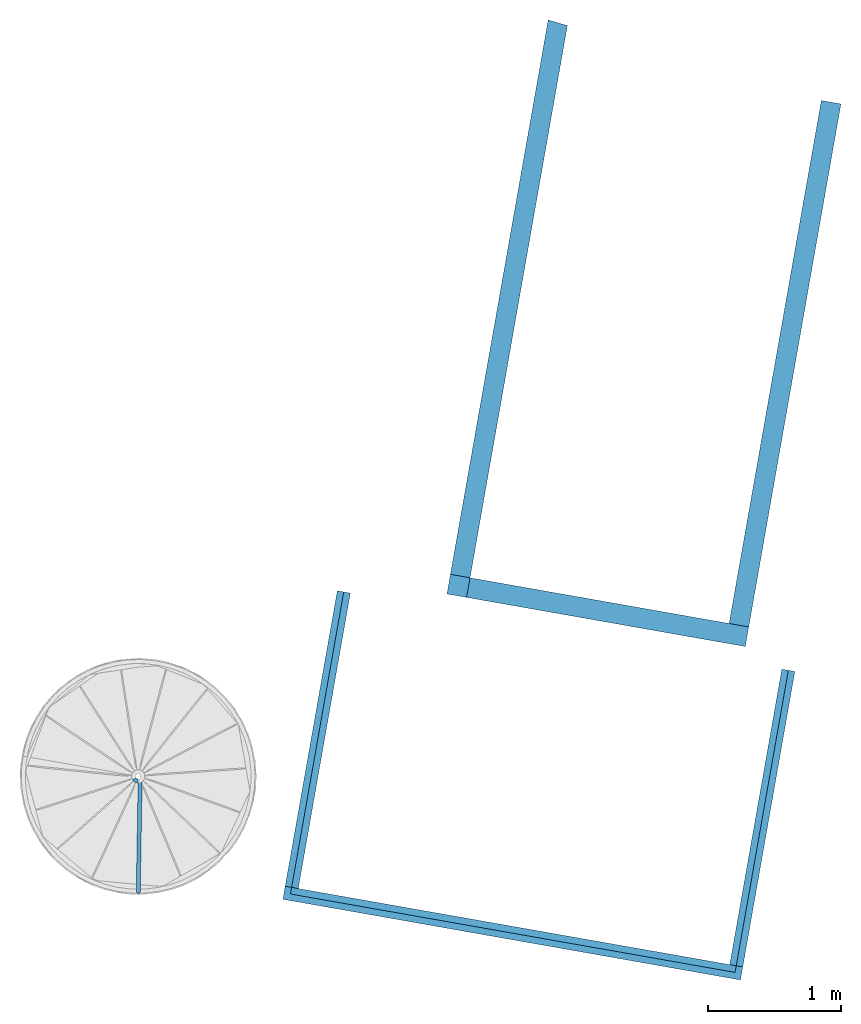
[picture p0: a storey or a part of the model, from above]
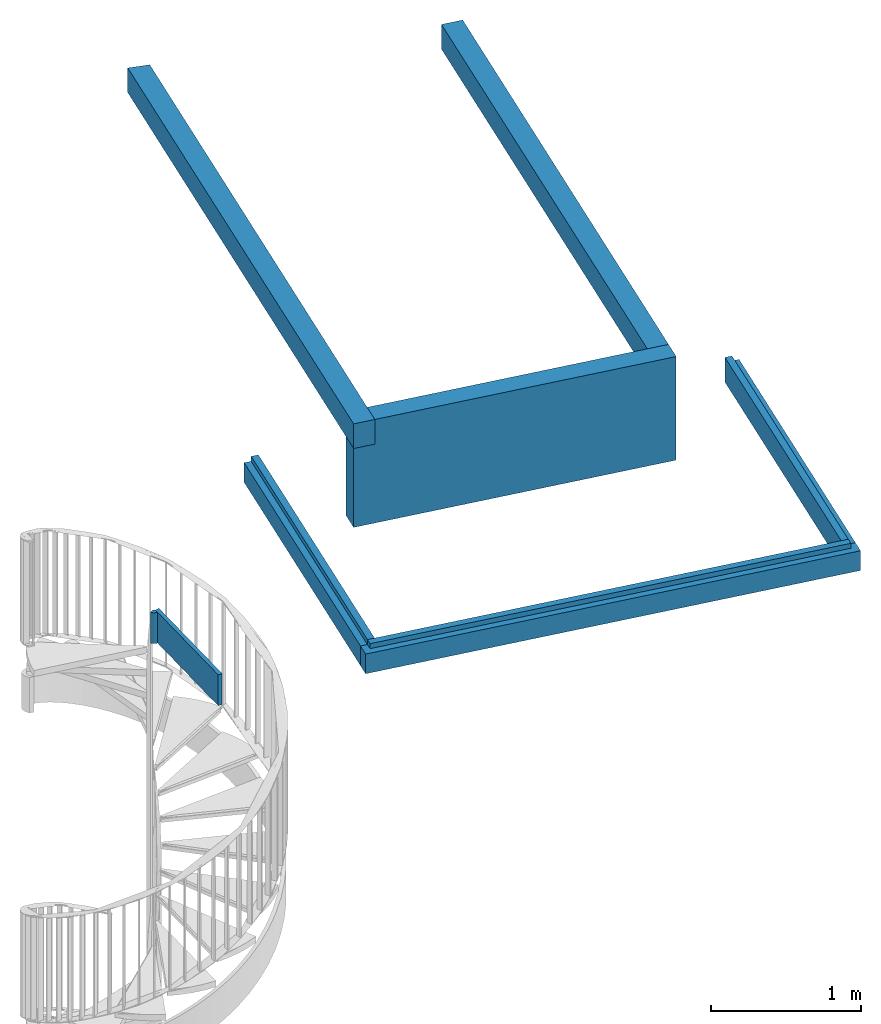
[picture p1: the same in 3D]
Properties of the parts of a building model (IFC2X3), part 2 of 3

# IfcPlate: 31_CWP_glas_1 (26)
Name (System Panel:31_CWP_glas_1:...) | Group
2317196 | Model Group:vliesgevel C:2317233
2317197 | Model Group:vliesgevel C:2317233
2317198 | Model Group:vliesgevel C:2317233
2317199 | Model Group:vliesgevel C:2317233
2317200 | Model Group:vliesgevel C:2317233
2317214 | Model Group:vliesgevel C:2317233
2317215 | Model Group:vliesgevel C:2317233
2317216 | Model Group:vliesgevel C:2317233
2317217 | Model Group:vliesgevel C:2317233
2317218 | Model Group:vliesgevel C:2317233
2317219 | Model Group:vliesgevel C:2317233
2940402 | Model Group:vliesgevel A:2917414
2940415 | Model Group:vliesgevel A:2917414
2940420 | Model Group:vliesgevel A:2917414
2940421 | Model Group:vliesgevel A:2917414
2940422 | Model Group:vliesgevel A:2917414
2940423 | Model Group:vliesgevel A:2917414
2940434 | Model Group:vliesgevel A:2917414
2940435 | Model Group:vliesgevel A:2917414
2940436 | Model Group:vliesgevel A:2917414
2940437 | Model Group:vliesgevel A:2917414

# IfcPlate: 31_CWP_glas_2 (23)
Type - PredefinedType: CURTAIN_PANEL; Material: <Unnamed> 24 mm
Type - Pset_PlateCommon - IsExternal: no; Reference: 31_CWP_glas_2
Type - Pset_ProductRequirements - Category: Curtain Panels
Type - Pset_QuantityTakeOff - Reference: 31_CWP_glas_2
Classification: 31.10 buitenwandopeningen; niet gevuld, algemeen (verzamelniveau) (Uniformat)
Pset_PlateCommon - IsExternal: yes
Name (System Panel:31_CWP_glas_2:...) | In | Group
2287267 | 01 eerste verdieping | Model Group:H07:2287249
2760791 | 00 begane grond | Model Group:H08:2161338
2760801 | 00 begane grond | Model Group:H08:2161338
2760811 | 00 begane grond | Model Group:H08:2161338
2760821 | 00 begane grond | Model Group:H08:2161338
2760831 | 00 begane grond | Model Group:H08:2161338
2760841 | 00 begane grond | Model Group:H08:2161338
2760851 | 00 begane grond | Model Group:H08:2161338
2760861 | 00 begane grond | Model Group:H08:2161338
2760871 | 00 begane grond | Model Group:H08:2161338
2760881 | 00 begane grond | Model Group:H08:2161338
2760891 | 00 begane grond | Model Group:H08:2161338
2761306 | 02 tweede verdieping | Model Group:H09:1979223
2761316 | 02 tweede verdieping | Model Group:H09:1979223
2763742 | 02 tweede verdieping | Model Group:H10:2055879
2763752 | 02 tweede verdieping | Model Group:H10:2055879
2763762 | 02 tweede verdieping | Model Group:H10:2055879
2763772 | 02 tweede verdieping | Model Group:H10:2055879
2763782 | 02 tweede verdieping | Model Group:H10:2055879
2763792 | 02 tweede verdieping | Model Group:H10:2055879
2764323 | 02 tweede verdieping | Model Group:H11:2764105
2764333 | 02 tweede verdieping | Model Group:H11:2764105
2764343 | 02 tweede verdieping | Model Group:H11:2764105

# IfcPlate: 32_CWP_glas (14)
In: 00 begane grond
Type - PredefinedType: CURTAIN_PANEL; Material: <Unnamed> 24 mm
Type - Pset_PlateCommon - IsExternal: no; Reference: 32_CWP_glas
Type - Pset_ProductRequirements - Category: Curtain Panels
Type - Pset_QuantityTakeOff - Reference: 32_CWP_glas
Pset_PlateCommon - IsExternal: yes
Name (System Panel:32_CWP_glas:...) | Classification | Group
1745525 | 32.40 binnenwandopeningen; gevuld met puien, algemeen (verzamelniveau) (Uniformat) | Model Group:Vliesgevel B:2773624
2534468 | 32.40 binnenwandopeningen; gevuld met puien, algemeen (verzamelniveau) (Uniformat) | Model Group:Vliesgevel B:2773624
2532248 | 32.40 binnenwandopeningen; gevuld met puien, algemeen (verzamelniveau) (Uniformat) | Model Group:Vliesgevel B:2773624
2534469 | 32.40 binnenwandopeningen; gevuld met puien, algemeen (verzamelniveau) (Uniformat) | Model Group:Vliesgevel B:2773624
2532249 | 32.40 binnenwandopeningen; gevuld met puien, algemeen (verzamelniveau) (Uniformat) | Model Group:Vliesgevel B:2773624
2534730 | 32.40 binnenwandopeningen; gevuld met puien, algemeen (verzamelniveau) (Uniformat) | Model Group:Vliesgevel B:2773624
2533499 | 32.40 binnenwandopeningen; gevuld met puien, algemeen (verzamelniveau) (Uniformat) | Model Group:Vliesgevel B:2773624
2534470 | 32.40 binnenwandopeningen; gevuld met puien, algemeen (verzamelniveau) (Uniformat) | Model Group:Vliesgevel B:2773624
2533500 | 32.40 binnenwandopeningen; gevuld met puien, algemeen (verzamelniveau) (Uniformat) | Model Group:Vliesgevel B:2773624
2534731 | 32.40 binnenwandopeningen; gevuld met puien, algemeen (verzamelniveau) (Uniformat) | Model Group:Vliesgevel B:2773624
1745975 | 32 binnenwandopeningen (Uniformat)
1745978 | 32 binnenwandopeningen (Uniformat)
1745980 | 32 binnenwandopeningen (Uniformat)
1766173 | 32 binnenwandopeningen (Uniformat)

# IfcRailing: Railing:NLRS_90_RA_LB_hekwerk panelen_laag (2)
Classification: 34.11 balustrades en leuningen; balustrades, binnenbalustrades (Uniformat); Material: h2_staal_gen; Group: Model Group:trap naar kelder:2174486
Pset_ProductRequirements - Category: Railings
Pset_QuantityTakeOff - Reference: NLRS_90_RA_LB_hekwerk panelen_laag
Pset_RailingCommon - IsExternal: no; Reference: NLRS_90_RA_LB_hekwerk panelen_laag; Height: 1219.2 mm
Name (Railing:NLRS_90_RA_LB_hekwerk panelen_laag:...) | In
2174470 | -1 kelder
2174483 | 00 begane grond

# IfcRailing: Railing:NLRS_90_RA_LB_hekwerk spijlen staal, Railing:NLRS_90_RA_LB_hekwerk spijlen staal:2887061
In: 02 tweede verdieping
Classification: 34.11 balustrades en leuningen; balustrades, binnenbalustrades (Uniformat); Material: h2_staal_gen
Pset_ProductRequirements - Category: Railings
Pset_QuantityTakeOff - Reference: NLRS_90_RA_LB_hekwerk spijlen staal
Pset_RailingCommon - IsExternal: no; Reference: NLRS_90_RA_LB_hekwerk spijlen staal; Height: 1219.2 mm

# IfcRailing: Railing:NLRS_90_RA_LB_hekwerk spijlen staal + bordes strip, Railing:NLRS_90_RA_LB_hekwerk spijlen staal + bordes strip:2925256
In: 02 tweede verdieping
Classification: 34.11 balustrades en leuningen; balustrades, binnenbalustrades (Uniformat); Material: h2_staal_gen
Pset_ProductRequirements - Category: Railings
Pset_QuantityTakeOff - Reference: NLRS_90_RA_LB_hekwerk spijlen staal + bordes strip
Pset_RailingCommon - IsExternal: no; Reference: NLRS_90_RA_LB_hekwerk spijlen staal + bordes strip; Height: 1219.2 mm

# IfcRailing: Railing:NLRS_90_RA_LB_hekwerk spijlen staal + trapboom strip, Railing:NLRS_90_RA_LB_hekwerk spijlen staal + trapboom strip:2926586
In: 00 begane grond
Classification: 34.11 balustrades en leuningen; balustrades, binnenbalustrades (Uniformat); Material: h2_staal_gen
Pset_ProductRequirements - Category: Railings
Pset_QuantityTakeOff - Reference: NLRS_90_RA_LB_hekwerk spijlen staal + trapboom strip
Pset_RailingCommon - IsExternal: no; Reference: NLRS_90_RA_LB_hekwerk spijlen staal + trapboom strip; Height: 1219.2 mm

# IfcRailing: Railing:NLRS_90_RA_LB_hekwerk spijlen staal +trapboom (2)
In: 02 tweede verdieping
Classification: 34.11 balustrades en leuningen; balustrades, binnenbalustrades (Uniformat); Material: h2_staal_gen
Pset_ProductRequirements - Category: Railings
Pset_QuantityTakeOff - Reference: NLRS_90_RA_LB_hekwerk spijlen staal +trapboom
Pset_RailingCommon - IsExternal: no; Reference: NLRS_90_RA_LB_hekwerk spijlen staal +trapboom; Height: 1219.2 mm
Name (Railing:NLRS_90_RA_LB_hekwerk spijlen staal +trapboom:...)
2871537
2871541

# IfcRailing: Railing:RBM_RA_glasbalustrade (8)
Classification: C2010400 (Uniformat); Material: Glass_RIPO
Pset_ProductRequirements - Category: Railings
Pset_QuantityTakeOff - Reference: RBM_RA_glasbalustrade
Pset_RailingCommon - IsExternal: no; Reference: RBM_RA_glasbalustrade; Height: 1066.8 mm
Name (Railing:RBM_RA_glasbalustrade:...) | In
2876911 | 02 tweede verdieping
2877435 | 00 begane grond
2878266 | 02 tweede verdieping
2878645 | 02 tweede verdieping
2879326 | 02 tweede verdieping
2879408 | 02 tweede verdieping
2879637 | 02 tweede verdieping
2879737 | 02 tweede verdieping

# IfcRailing: Railing:RBM_RA_glasbalustrade 02 TRAP (2)
Classification: C2010400 (Uniformat); Material: Glass_RIPO
Pset_ProductRequirements - Category: Railings
Pset_QuantityTakeOff - Reference: RBM_RA_glasbalustrade 02 TRAP
Pset_RailingCommon - IsExternal: no; Reference: RBM_RA_glasbalustrade 02 TRAP; Height: 1066.8 mm
Name (Railing:RBM_RA_glasbalustrade 02 TRAP:...) | In
2877431 | 00 begane grond
2878579 | 01 eerste verdieping

# IfcRailing: Railing:RBM_RA_handleuning (3)
Classification: C2010400 (Uniformat)
Pset_ProductRequirements - Category: Railings
Pset_QuantityTakeOff - Reference: RBM_RA_handleuning
Pset_RailingCommon - IsExternal: no; Reference: RBM_RA_handleuning; Height: 1066.8 mm
Name (Railing:RBM_RA_handleuning:...) | In
2879164 | 02 tweede verdieping
2879217 | 02 tweede verdieping
2879233 | 01 eerste verdieping

# IfcRoof: Basic Roof:Dak_isolatie goot, Basic Roof:Dak_isolatie goot:2599447
In: 03 dak
Classification: 27.10 daken; niet constructief, algemeen (verzamelniveau) (Uniformat)
Pset_ElementShading - Roughness: 304.8 mm
Pset_ProductRequirements - Category: Roofs
Pset_QuantityTakeOff - Reference: Dak_isolatie goot
Pset_RoofCommon - IsExternal: yes; Reference: Dak_isolatie goot; ProjectedArea: 5.72349 m2; TotalArea: 5.73957 m2

# IfcRoof: Basic Roof:RBM_27_RO_dakisolatie met afwerking_240mm (2)
Classification: 27.10 daken; niet constructief, algemeen (verzamelniveau) (Uniformat)
Pset_ElementShading - Roughness: 304.8 mm
Pset_ProductRequirements - Category: Roofs
Pset_QuantityTakeOff - Reference: RBM_27_RO_dakisolatie met afwerking_240mm
Pset_RoofCommon - IsExternal: yes; Reference: RBM_27_RO_dakisolatie met afwerking_240mm
Name (Basic Roof:RBM_27_RO_dakisolatie met afwerking_240mm:...) | In | ProjectedArea (m2) | TotalArea (m2)
2319589 | 03 dak | 268.647 | 269.401
2454118 | 02 tweede verdieping | 3.34901 | 3.34901

# IfcRoof: Basic Roof:RBM_27_RO_dakrand_gelamineerd, Basic Roof:RBM_27_RO_dakrand_gelamineerd:2143979
In: 03 dak
Classification: 47.23 dakafwerkingen; bekledingen, luifel bekledingen (Uniformat); Material: hout_accoya_gelamineerd 600 mm
Pset_ElementShading - Roughness: 304.8 mm
Pset_ProductRequirements - Category: Roofs
Pset_QuantityTakeOff - Reference: RBM_27_RO_dakrand_gelamineerd
Pset_RoofCommon - IsExternal: yes; Reference: RBM_27_RO_dakrand_gelamineerd; ProjectedArea: 449.378 m2; TotalArea: 9.75975 m2

# IfcRoof: Sloped Glazing:dakbalken (2)
In: 03 dak
Type - Pset_CurtainWallCommon - IsExternal: yes; Reference: dakbalken
Type - Pset_ProductRequirements - Category: Roofs
Type - Pset_QuantityTakeOff - Reference: dakbalken
Classification: 27.23 daken; constructief, luifels (Uniformat)
Pset_RoofCommon - IsExternal: yes; Reference: dakbalken
Name (Sloped Glazing:dakbalken:...) | ProjectedArea (m2)
2777888 | 54.3172
2777893 | 105.253

# IfcSlab: Basic Roof:Dak_isolatie goot, Basic Roof:Dak_isolatie goot:2599447
In: 03 dak
PredefinedType: ROOF; Classification: 27.10 daken; niet constructief, algemeen (verzamelniveau) (Uniformat); Material: RBM_n7_dakisolatie_80 80 mm
Pset_ElementShading - Roughness: 304.8 mm
Pset_ProductRequirements - Category: Roofs
Pset_QuantityTakeOff - Reference: Dak_isolatie goot; sets with these values: 2
Pset_SlabCommon - IsExternal: yes; Reference: Dak_isolatie goot; ThermalTransmittance: 1000000000000000019884624838656 kg/K/s3; PitchAngle: 4.29718 deg

# IfcSlab: Basic Roof:RBM_27_RO_dakisolatie met afwerking_240mm (2)
PredefinedType: ROOF; Classification: 27.10 daken; niet constructief, algemeen (verzamelniveau) (Uniformat); Material: RBM_n7_dakisolatie_240mm 240 mm
Pset_ElementShading - Roughness: 304.8 mm
Pset_ProductRequirements - Category: Roofs
Pset_QuantityTakeOff - Reference: RBM_27_RO_dakisolatie met afwerking_240mm; sets with these values: 2
Pset_SlabCommon - IsExternal: yes; Reference: RBM_27_RO_dakisolatie met afwerking_240mm; ThermalTransmittance: 1000000000000000019884624838656 kg/K/s3
Name (Basic Roof:RBM_27_RO_dakisolatie met afwerking_240mm:...) | In | PitchAngle (deg)
2319589 | 03 dak | 4.29718
2454118 | 02 tweede verdieping | 0

# IfcSlab: Floor:RBM_23_FL_Fermacell_zwevende_dekvloer (2)
In: 01 eerste verdieping
Type - PredefinedType: FLOOR; Material: vloerafwerking pvc 10 mm, Zwevende dekvloer Fermacell 35 mm
Type - Pset_ElementShading - Roughness: 304.8 mm
Type - Pset_ProductRequirements - Category: Floors
Type - Pset_QuantityTakeOff - Reference: RBM_23_FL_Fermacell_zwevende_dekvloer
Type - Pset_ReinforcementBarPitchOfSlab - Description: Fermacell zwevende dekvloer; Reference: RBM_23_FL_Fermacell_zwevende_dekvloer
Type - Pset_SlabCommon - IsExternal: no; Reference: RBM_23_FL_Fermacell_zwevende_dekvloer; ThermalTransmittance: 104.6 kg/K/s3
Classification: 23.21 vloeren; constructief, vrijdragende vloeren (Uniformat)
Pset_SlabCommon - LoadBearing: no; PitchAngle: 0 deg
Name (Floor:RBM_23_FL_Fermacell_zwevende_dekvloer:...)
2631502
2645933

# IfcSlab: Floor:RBM_23_FL_balklaag dak_71x246mm h.o.h.400mm, Floor:RBM_23_FL_balklaag dak_71x246mm h.o.h.400mm:2453909
In: 02 tweede verdieping
Type - PredefinedType: FLOOR; Material: RBM_i2_hout_vuren_gen 246 mm
Type - Pset_ElementShading - Roughness: 304.8 mm
Type - Pset_ProductRequirements - Category: Floors
Type - Pset_QuantityTakeOff - Reference: RBM_23_FL_balklaag dak_71x246mm h.o.h.400mm
Type - Pset_ReinforcementBarPitchOfSlab - Description: vloer, generiek; Reference: RBM_23_FL_balklaag dak_71x246mm h.o.h.400mm
Type - Pset_SlabCommon - IsExternal: no; Reference: RBM_23_FL_balklaag dak_71x246mm h.o.h.400mm; ThermalTransmittance: 0.487805 kg/K/s3
Classification: 23.20 vloeren; constructief, algemeen (verzamelniveau) (Uniformat)
Pset_SlabCommon - LoadBearing: no; PitchAngle: 0 deg

# IfcSlab: Floor:RBM_23_FL_balklaag dak_71x271, h.o.h. 400 (3)
Type - PredefinedType: FLOOR; Material: ISR_Multiplex 18 mm, RBM_i2_hout_vuren_gen 271 mm
Type - Pset_ElementShading - Roughness: 304.8 mm
Type - Pset_ProductRequirements - Category: Floors
Type - Pset_QuantityTakeOff - Reference: RBM_23_FL_balklaag dak_71x271, h.o.h. 400
Type - Pset_ReinforcementBarPitchOfSlab - Description: vloer, generiek; Reference: RBM_23_FL_balklaag dak_71x271, h.o.h. 400
Type - Pset_SlabCommon - IsExternal: no; Reference: RBM_23_FL_balklaag dak_71x271, h.o.h. 400; ThermalTransmittance: 0.442804 kg/K/s3
Classification: 23.20 vloeren; constructief, algemeen (verzamelniveau) (Uniformat)
Pset_SlabCommon - LoadBearing: no; PitchAngle: 0 deg
Name (Floor:RBM_23_FL_balklaag dak_71x271, h.o.h. 400:...) | In
1974393 | 02 tweede verdieping
1977292 | 01 eerste verdieping
2748788 | 01 eerste verdieping

# IfcSlab: Floor:RBM_23_FL_dakisolatie 30 mm (2)
In: 01 eerste verdieping
Type - PredefinedType: FLOOR; Material: RBM_n7_dakisolatie_gen 50 mm
Type - Pset_ElementShading - Roughness: 304.8 mm
Type - Pset_ProductRequirements - Category: Floors
Type - Pset_QuantityTakeOff - Reference: RBM_23_FL_dakisolatie 30 mm
Type - Pset_ReinforcementBarPitchOfSlab - Description: vloer, generiek; Reference: RBM_23_FL_dakisolatie 30 mm
Type - Pset_SlabCommon - IsExternal: no; Reference: RBM_23_FL_dakisolatie 30 mm
Classification: 23.20 vloeren; constructief, algemeen (verzamelniveau) (Uniformat)
Pset_SlabCommon - LoadBearing: no; PitchAngle: 0 deg
Name (Floor:RBM_23_FL_dakisolatie 30 mm:...)
2748825
2749276

# IfcSlab: Floor:RBM_23_FL_dakisolatie 30 mm afschot 15mm/m1, Floor:RBM_23_FL_dakisolatie 30 mm afschot 15mm/m1:2749066
In: 02 tweede verdieping
Type - PredefinedType: FLOOR
Type - Pset_ElementShading - Roughness: 304.8 mm
Type - Pset_ProductRequirements - Category: Floors
Type - Pset_QuantityTakeOff - Reference: RBM_23_FL_dakisolatie 30 mm afschot 15mm/m1
Type - Pset_ReinforcementBarPitchOfSlab - Description: vloer, generiek; Reference: RBM_23_FL_dakisolatie 30 mm afschot 15mm/m1
Type - Pset_SlabCommon - IsExternal: no; Reference: RBM_23_FL_dakisolatie 30 mm afschot 15mm/m1
Classification: 23.20 vloeren; constructief, algemeen (verzamelniveau) (Uniformat); Material: RBM_n7_dakisolatie_gen
Pset_SlabCommon - LoadBearing: no

# IfcSlab: Floor:RBM_23_FL_gewapende druklaag gevlinderd (2)
In: 00 begane grond
Type - PredefinedType: FLOOR; Material: RBM_f2_beton_ihwg C20-25 80 mm
Type - Pset_ElementShading - Roughness: 304.8 mm
Type - Pset_ProductRequirements - Category: Floors
Type - Pset_QuantityTakeOff - Reference: RBM_23_FL_gewapende druklaag gevlinderd
Type - Pset_ReinforcementBarPitchOfSlab - Description: vloer, generiek; Reference: RBM_23_FL_gewapende druklaag gevlinderd
Type - Pset_SlabCommon - IsExternal: no; Reference: RBM_23_FL_gewapende druklaag gevlinderd; ThermalTransmittance: 13.075 kg/K/s3
Classification: 23.20 vloeren; constructief, algemeen (verzamelniveau) (Uniformat)
Pset_SlabCommon - LoadBearing: no; PitchAngle: 0 deg
Name (Floor:RBM_23_FL_gewapende druklaag gevlinderd:...)
2798566
2936558

# IfcSlab: Floor:RBM_23_FL_gewapende druklaag gevlinderd+ afwerking (2)
In: 00 begane grond
Type - PredefinedType: FLOOR; Material: vloerafwerking pvc 10 mm, RBM_f2_beton_ihwg C20-25 80 mm
Type - Pset_ElementShading - Roughness: 304.8 mm
Type - Pset_ProductRequirements - Category: Floors
Type - Pset_QuantityTakeOff - Reference: RBM_23_FL_gewapende druklaag gevlinderd+ afwerking
Type - Pset_ReinforcementBarPitchOfSlab - Description: vloer, generiek; Reference: RBM_23_FL_gewapende druklaag gevlinderd+ afwerking
Type - Pset_SlabCommon - IsExternal: no; Reference: RBM_23_FL_gewapende druklaag gevlinderd+ afwerking; ThermalTransmittance: 11.6222 kg/K/s3
Classification: 23.20 vloeren; constructief, algemeen (verzamelniveau) (Uniformat)
Pset_SlabCommon - LoadBearing: no; PitchAngle: 0 deg
Name (Floor:RBM_23_FL_gewapende druklaag gevlinderd+ afwerking:...)
2793050
2796847

# IfcSlab: Floor:RBM_23_FL_gewapende druklaag gevlinderd+ afwerking, Floor:RBM_23_FL_gewapende druklaag gevlinderd+ afwerking:2540512
In: 00 begane grond
Type - PredefinedType: FLOOR
Type - Pset_ElementShading - Roughness: 304.8 mm
Type - Pset_ProductRequirements - Category: Floors
Type - Pset_QuantityTakeOff - Reference: RBM_23_FL_gewapende druklaag gevlinderd+ afwerking
Type - Pset_ReinforcementBarPitchOfSlab - Description: vloer, generiek; Reference: RBM_23_FL_gewapende druklaag gevlinderd+ afwerking
Type - Pset_SlabCommon - IsExternal: no; Reference: RBM_23_FL_gewapende druklaag gevlinderd+ afwerking; ThermalTransmittance: 11.6222 kg/K/s3
Classification: 23.20 vloeren; constructief, algemeen (verzamelniveau) (Uniformat); Material: vloerafwerking pvc, RBM_f2_beton_ihwg C20-25
Pset_SlabCommon - LoadBearing: no

# IfcSlab: Floor:RBM_23_FL_houten kanaalplaat-320mm (2)
Type - PredefinedType: FLOOR; Material: RBM_i4_multiplex_beplating 320 mm
Type - Pset_ElementShading - Roughness: 304.8 mm
Type - Pset_ProductRequirements - Category: Floors
Type - Pset_QuantityTakeOff - Reference: RBM_23_FL_houten kanaalplaat-320mm
Type - Pset_ReinforcementBarPitchOfSlab - Description: prefab houten kanaalplaatvloer, vrijdragend; Reference: RBM_23_FL_houten kanaalplaat-320mm
Type - Pset_SlabCommon - IsExternal: no; Reference: RBM_23_FL_houten kanaalplaat-320mm; ThermalTransmittance: 0.33125 kg/K/s3
Classification: 23.21 vloeren; constructief, vrijdragende vloeren (Uniformat)
Pset_SlabCommon - LoadBearing: no; PitchAngle: 0 deg
Name (Floor:RBM_23_FL_houten kanaalplaat-320mm:...) | In
1655074 | 02 tweede verdieping
1733735 | 03 dak

# IfcSlab: Floor:RBM_23_FL_houten vloer-brug (2)
Type - PredefinedType: FLOOR; Material: traphout 50 mm
Type - Pset_ElementShading - Roughness: 304.8 mm
Type - Pset_ProductRequirements - Category: Floors
Type - Pset_QuantityTakeOff - Reference: RBM_23_FL_houten vloer-brug
Type - Pset_ReinforcementBarPitchOfSlab - Description: vloer, generiek; Reference: RBM_23_FL_houten vloer-brug
Type - Pset_SlabCommon - IsExternal: no; Reference: RBM_23_FL_houten vloer-brug; ThermalTransmittance: 2.4 kg/K/s3
Classification: 23.20 vloeren; constructief, algemeen (verzamelniveau) (Uniformat)
Pset_SlabCommon - LoadBearing: no; PitchAngle: 0 deg
Name (Floor:RBM_23_FL_houten vloer-brug:...) | In
1654735 | 01 eerste verdieping
1659754 | 02 tweede verdieping

# IfcSlab: Floor:RBM_23_FL_kanaalplaat-200mm_gen_rsf (2)
In: 00 begane grond
Type - PredefinedType: FLOOR; Material: RBM_f2_beton_prefab_gen 260 mm
Type - Pset_ElementShading - Roughness: 304.8 mm
Type - Pset_ProductRequirements - Category: Floors
Type - Pset_QuantityTakeOff - Reference: RBM_23_FL_kanaalplaat-200mm_gen_rsf
Type - Pset_ReinforcementBarPitchOfSlab - Description: prefab kanaalplaatvloer, vrijdragend; Reference: RBM_23_FL_kanaalplaat-200mm_gen_rsf
Type - Pset_SlabCommon - IsExternal: no; Reference: RBM_23_FL_kanaalplaat-200mm_gen_rsf; ThermalTransmittance: 4.02308 kg/K/s3
Classification: 23.21 vloeren; constructief, vrijdragende vloeren (Uniformat)
Pset_SlabCommon - LoadBearing: no; PitchAngle: 0 deg
Name (Floor:RBM_23_FL_kanaalplaat-200mm_gen_rsf:...)
1655273
2801751

# IfcSlab: Floor:RBM_23_FL_kanaalplaat-260mm+druklaag-80mm, Floor:RBM_23_FL_kanaalplaat-260mm+druklaag-80mm:1655409
In: 00 begane grond
Type - PredefinedType: FLOOR; Material: vloerafwerking pvc 10 mm, RBM_f2_beton_ihwg_gen 60 mm, RBM_f2_beton_ihwg C20-25 70 mm, RBM_f2_beton_prefab_gen 260 mm, RBM_n7_isolatie_EPS 140 mm
Type - Pset_ElementShading - Roughness: 304.8 mm
Type - Pset_ProductRequirements - Category: Floors
Type - Pset_QuantityTakeOff - Reference: RBM_23_FL_kanaalplaat-260mm+druklaag-80mm
Type - Pset_ReinforcementBarPitchOfSlab - Description: prefab kanaalplaatvloer, vrijdragend; Reference: RBM_23_FL_kanaalplaat-260mm+druklaag-80mm
Type - Pset_SlabCommon - IsExternal: no; Reference: RBM_23_FL_kanaalplaat-260mm+druklaag-80mm; ThermalTransmittance: 0.228185 kg/K/s3
Classification: 23.21 vloeren; constructief, vrijdragende vloeren (Uniformat)
Pset_SlabCommon - LoadBearing: no; PitchAngle: 0 deg

# IfcSlab: Floor:RBM_23_FL_kanaalplaat-260mm+druklaag-80mm overbrugging, Floor:RBM_23_FL_kanaalplaat-260mm+druklaag-80mm overbrugging:2235945
In: 00 begane grond
Type - PredefinedType: FLOOR; Material: vloerafwerking pvc 10 mm, RBM_f2_beton_ihwg_gen 80 mm, RBM_n7_isolatie_hsb_245 540 mm, RBM_f2_beton_prefab_gen 260 mm
Type - Pset_ElementShading - Roughness: 304.8 mm
Type - Pset_ProductRequirements - Category: Floors
Type - Pset_QuantityTakeOff - Reference: RBM_23_FL_kanaalplaat-260mm+druklaag-80mm overbrugging
Type - Pset_ReinforcementBarPitchOfSlab - Description: prefab kanaalplaatvloer, vrijdragend; Reference: RBM_23_FL_kanaalplaat-260mm+druklaag-80mm overbrugging
Type - Pset_SlabCommon - IsExternal: no; Reference: RBM_23_FL_kanaalplaat-260mm+druklaag-80mm overbrugging; ThermalTransmittance: 2.98857 kg/K/s3
Classification: 23.21 vloeren; constructief, vrijdragende vloeren (Uniformat)
Pset_SlabCommon - LoadBearing: no; PitchAngle: 0 deg

# IfcSlab: Floor:RBM_23_FL_tempex 690mm (2)
In: 00 begane grond
Type - PredefinedType: FLOOR; Material: RBM_n7_isolatie_hsb_245 560 mm
Type - Pset_ElementShading - Roughness: 304.8 mm
Type - Pset_ProductRequirements - Category: Floors
Type - Pset_QuantityTakeOff - Reference: RBM_23_FL_tempex 690mm
Type - Pset_ReinforcementBarPitchOfSlab - Description: vloer, generiek; Reference: RBM_23_FL_tempex 690mm
Type - Pset_SlabCommon - IsExternal: no; Reference: RBM_23_FL_tempex 690mm
Classification: 23.20 vloeren; constructief, algemeen (verzamelniveau) (Uniformat)
Pset_SlabCommon - LoadBearing: no; PitchAngle: 0 deg
Name (Floor:RBM_23_FL_tempex 690mm:...)
2795189
2799929

# IfcSlab: Floor:RBM_23_FL_tempex 790, Floor:RBM_23_FL_tempex 790:2795876
In: 00 begane grond
Type - PredefinedType: FLOOR; Material: RBM_n7_isolatie_hsb_245 790 mm
Type - Pset_ElementShading - Roughness: 304.8 mm
Type - Pset_ProductRequirements - Category: Floors
Type - Pset_QuantityTakeOff - Reference: RBM_23_FL_tempex 790
Type - Pset_ReinforcementBarPitchOfSlab - Description: vloer, generiek; Reference: RBM_23_FL_tempex 790
Type - Pset_SlabCommon - IsExternal: no; Reference: RBM_23_FL_tempex 790
Classification: 23.20 vloeren; constructief, algemeen (verzamelniveau) (Uniformat)
Pset_SlabCommon - LoadBearing: no; PitchAngle: 0 deg

# IfcSlab: Floor:RBM_23_FL_tempex 800mm, Floor:RBM_23_FL_tempex 800mm:1982200
In: 00 begane grond
Type - PredefinedType: FLOOR; Material: RBM_n7_isolatie_hsb_245 800 mm
Type - Pset_ElementShading - Roughness: 304.8 mm
Type - Pset_ProductRequirements - Category: Floors
Type - Pset_QuantityTakeOff - Reference: RBM_23_FL_tempex 800mm
Type - Pset_ReinforcementBarPitchOfSlab - Description: vloer, generiek; Reference: RBM_23_FL_tempex 800mm
Type - Pset_SlabCommon - IsExternal: no; Reference: RBM_23_FL_tempex 800mm
Classification: 23.20 vloeren; constructief, algemeen (verzamelniveau) (Uniformat)
Pset_SlabCommon - LoadBearing: no

# IfcSlab: Floor:RBM_23_FL_underlayment 19 mm, Floor:RBM_23_FL_underlayment 19 mm:1659719
In: 01 eerste verdieping
Type - PredefinedType: FLOOR; Material: ISR_Multiplex 19 mm
Type - Pset_ElementShading - Roughness: 304.8 mm
Type - Pset_ProductRequirements - Category: Floors
Type - Pset_QuantityTakeOff - Reference: RBM_23_FL_underlayment 19 mm
Type - Pset_ReinforcementBarPitchOfSlab - Description: vloer, generiek; Reference: RBM_23_FL_underlayment 19 mm
Type - Pset_SlabCommon - IsExternal: no; Reference: RBM_23_FL_underlayment 19 mm
Classification: 23.20 vloeren; constructief, algemeen (verzamelniveau) (Uniformat)
Pset_SlabCommon - LoadBearing: no; PitchAngle: 0 deg

# IfcSlab: Floor:RBM_43_FL_betontegels op dragers (2)
In: 02 tweede verdieping
Type - PredefinedType: FLOOR; Material: RBM_f2_betontegels 30 mm, RBM_n7_isolatie_zwevende dekvloer 20 mm
Type - Pset_ElementShading - Roughness: 304.8 mm
Type - Pset_ProductRequirements - Category: Floors
Type - Pset_QuantityTakeOff - Reference: RBM_43_FL_betontegels op dragers
Type - Pset_ReinforcementBarPitchOfSlab - Description: betontegels op dragers; Reference: RBM_43_FL_betontegels op dragers
Type - Pset_SlabCommon - IsExternal: no; Reference: RBM_43_FL_betontegels op dragers; ThermalTransmittance: 1.66636 kg/K/s3
Classification: 43.21 vloerafwerkingen; niet verhoogd, afwerklagen (Uniformat)
Pset_SlabCommon - LoadBearing: no; IsExternal: yes; PitchAngle: 0 deg
Name (Floor:RBM_43_FL_betontegels op dragers:...)
2874446
2880596

# IfcSlab: Floor:RBM_43_FL_bordes trap, Floor:RBM_43_FL_bordes trap:2880514
In: 02 tweede verdieping
Type - PredefinedType: FLOOR; Material: ISR_RVS 50 mm
Type - Pset_ElementShading - Roughness: 304.8 mm
Type - Pset_ProductRequirements - Category: Floors
Type - Pset_QuantityTakeOff - Reference: RBM_43_FL_bordes trap
Type - Pset_ReinforcementBarPitchOfSlab - Description: roostervloer; Reference: RBM_43_FL_bordes trap
Type - Pset_SlabCommon - IsExternal: no; Reference: RBM_43_FL_bordes trap
Classification: 43.21 vloerafwerkingen; niet verhoogd, afwerklagen (Uniformat)
Pset_SlabCommon - LoadBearing: no; PitchAngle: 0 deg

# IfcSlab: Floor:RBM_43_FL_cementdekvloer-50mm_gen_rsf, Floor:RBM_43_FL_cementdekvloer-50mm_gen_rsf:2319789
In: 00 begane grond
Type - PredefinedType: FLOOR; Material: RBM_f2_beton_ihwg_gen 100 mm
Type - Pset_ElementShading - Roughness: 304.8 mm
Type - Pset_ProductRequirements - Category: Floors
Type - Pset_QuantityTakeOff - Reference: RBM_43_FL_cementdekvloer-50mm_gen_rsf
Type - Pset_ReinforcementBarPitchOfSlab - Description: zandcement dekvloer; Reference: RBM_43_FL_cementdekvloer-50mm_gen_rsf
Type - Pset_SlabCommon - IsExternal: no; Reference: RBM_43_FL_cementdekvloer-50mm_gen_rsf; ThermalTransmittance: 10.46 kg/K/s3
Classification: 43.21 vloerafwerkingen; niet verhoogd, afwerklagen (Uniformat)
Pset_SlabCommon - LoadBearing: no; PitchAngle: 0 deg

# IfcSlab: Floor:RBM_43_FL_roostervloer (2)
In: 00 begane grond
Type - PredefinedType: FLOOR; Material: RBM_h2_staal_vloerrooster 50 mm
Type - Pset_ElementShading - Roughness: 304.8 mm
Type - Pset_ProductRequirements - Category: Floors
Type - Pset_QuantityTakeOff - Reference: RBM_43_FL_roostervloer
Type - Pset_ReinforcementBarPitchOfSlab - Description: roostervloer; Reference: RBM_43_FL_roostervloer
Type - Pset_SlabCommon - IsExternal: no; Reference: RBM_43_FL_roostervloer
Classification: 43.21 vloerafwerkingen; niet verhoogd, afwerklagen (Uniformat)
Pset_SlabCommon - LoadBearing: no; PitchAngle: 0 deg
Name (Floor:RBM_43_FL_roostervloer:...)
2876685
2876763

# IfcStair: Assembled Stair:RBM_24_ST_stalen vluchttrap (2)
Classification: 24.11 trappen en hellingen; trappen, rechte steektrappen (Uniformat)
Pset_ProductRequirements - Category: Stairs
Pset_QuantityTakeOff - Reference: RBM_24_ST_stalen vluchttrap
Pset_StairCommon - IsExternal: no; Reference: RBM_24_ST_stalen vluchttrap
Name (Assembled Stair:Stair:...) | In | NumberOfRiser | NumberOfTreads | RiserHeight (mm) | TreadLength (mm)
2870841 | 02 tweede verdieping | 8 | 7 | 205.833 | 185
2925880 | 00 begane grond | 20 | 19 | 185 | 170

# IfcStair: Assembled Stair:RBM_ST_houten trap (2)
Classification: 24.11 trappen en hellingen; trappen, rechte steektrappen (Uniformat)
Pset_ProductRequirements - Category: Stairs
Pset_QuantityTakeOff - Reference: RBM_ST_houten trap
Pset_StairCommon - IsExternal: no; Reference: RBM_ST_houten trap
Name (Assembled Stair:Stair:...) | In | NumberOfRiser | NumberOfTreads | RiserHeight (mm) | TreadLength (mm)
1659339 | 01 eerste verdieping | 4 | 4 | 175 | 235
1742392 | 00 begane grond | 16 | 15 | 200 | 220

# IfcStair: Assembled Stair:Vluchttrap, Assembled Stair:Stair:2174468
In: -1 kelder
Classification: 24.11 trappen en hellingen; trappen, rechte steektrappen (Uniformat); Group: Model Group:trap naar kelder:2174486
Pset_ProductRequirements - Category: Stairs
Pset_QuantityTakeOff - Reference: Vluchttrap
Pset_StairCommon - IsExternal: no; Reference: Vluchttrap; NumberOfRiser: 20; NumberOfTreads: 19; RiserHeight: 200 mm; TreadLength: 185 mm

# IfcStairFlight: Non-Monolithic Run:40 mm persrooster (2)
Classification: 24.11 trappen en hellingen; trappen, rechte steektrappen (Uniformat); Material: RBM_h3_RVS
Pset_ProductRequirements - Category: Runs
Pset_QuantityTakeOff - Reference: 40 mm persrooster
Pset_StairFlightCommon - Reference: 40 mm persrooster; NosingLength: 40 mm
Name (Assembled Stair:Stair:...) | In | NumberOfRiser = Pset_StairFlightCommon, NumberOfRiser | NumberOfTreads = Pset_StairFlightCommon, NumberOfTreads | RiserHeight (mm) | TreadLength (mm) | Pset_StairFlightCommon, RiserHeight (mm) | Pset_StairFlightCommon, TreadLength (mm) = TreadLengthAtOffset (mm)
2870841 Run 1 | 02 tweede verdieping | 8 | 7 | 0.675306 | 0.606955 | 205.833 | 185
2925880 Run 1 | 00 begane grond | 20 | 19 | 0.606955 | 0.557743 | 185 | 170 | Pset_StairFlightCommon - WalkingLineOffset: 502.283 mm; WaistThickness: 1004.57 mm

# IfcStairFlight: Non-Monolithic Run:50mm Tread 13mm Riser, Assembled Stair:Stair:2174468 Run 1
In: -1 kelder
NumberOfRiser: 20; NumberOfTreads: 19; RiserHeight: 0.656168 mm; TreadLength: 0.606955 mm; Classification: 24.11 trappen en hellingen; trappen, rechte steektrappen (Uniformat); Group: Model Group:trap naar kelder:2174486
Pset_ProductRequirements - Category: Runs
Pset_QuantityTakeOff - Reference: 50mm Tread 13mm Riser
Pset_StairFlightCommon - Reference: 50mm Tread 13mm Riser; NumberOfRiser: 20; NumberOfTreads: 19; RiserHeight: 200 mm; TreadLength: 185 mm; NosingLength: 0 mm; WalkingLineOffset: 400 mm; TreadLengthAtOffset: 185 mm; WaistThickness: 800 mm

# IfcStairFlight: Non-Monolithic Run:RBM_ST_samengestelde houten trede (2)
Classification: 24.11 trappen en hellingen; trappen, rechte steektrappen (Uniformat); Material: traphout
Pset_ProductRequirements - Category: Runs
Pset_QuantityTakeOff - Reference: RBM_ST_samengestelde houten trede
Pset_StairFlightCommon - Reference: RBM_ST_samengestelde houten trede; NosingLength: 25 mm
Name (Assembled Stair:Stair:...) | In | NumberOfRiser = Pset_StairFlightCommon, NumberOfRiser | NumberOfTreads = Pset_StairFlightCommon, NumberOfTreads | RiserHeight (mm) | TreadLength (mm) | Pset_StairFlightCommon, RiserHeight (mm) | Pset_StairFlightCommon, TreadLength (mm) = TreadLengthAtOffset (mm) | WalkingLineOffset (mm) | WaistThickness (mm)
1659339 Run 1 | 01 eerste verdieping | 4 | 4 | 0.574147 | 0.770997 | 175 | 235 | 700 | 1400
1742392 Run 1 | 00 begane grond | 16 | 15 | 0.656168 | 0.721785 | 200 | 220 | 650 | 1300

# IfcWall: Basic Wall:22_WA_hsb-buitenwand_100mm 2, Basic Wall:22_WA_hsb-buitenwand_100mm 2:1771100
In: 00 begane grond
Type - PredefinedType: STANDARD; Material: RBM_n7_isolatie_hsb_100 100 mm
Type - Pset_ElementShading - Roughness: 304.8 mm
Type - Pset_ProductRequirements - Category: Walls
Type - Pset_QuantityTakeOff - Reference: 22_WA_hsb-buitenwand_100mm 2
Type - Pset_ReinforcementBarPitchOfWall - Reference: 22_WA_hsb-buitenwand_100mm 2
Type - Pset_WallCommon - IsExternal: no; Reference: 22_WA_hsb-buitenwand_100mm 2
Classification: 21.13 buitenwanden; niet constructief, systeemwanden (Uniformat); Material: RBM_n7_isolatie_hsb_100
Pset_QuantityTakeOff - sets with these values: 2
Pset_WallCommon - ExtendToStructure: no; LoadBearing: no

# IfcWall: Basic Wall:RBM_21_WA_170mm_geïsoleerde_kantplank, Basic Wall:RBM_21_WA_170mm_geïsoleerde_kantplank:1886998
In: 00 begane grond
Type - PredefinedType: STANDARD; Material: geisoleerde cementvezelplaat 20 mm, RBM_n7_isolatie_resol 150 mm
Type - Pset_ElementShading - Roughness: 304.8 mm
Type - Pset_ProductRequirements - Category: Walls
Type - Pset_QuantityTakeOff - Reference: RBM_21_WA_170mm_geïsoleerde_kantplank
Type - Pset_ReinforcementBarPitchOfWall - Description: isolatie, resolschuim; Reference: RBM_21_WA_170mm_geïsoleerde_kantplank
Type - Pset_WallCommon - IsExternal: no; Reference: RBM_21_WA_170mm_geïsoleerde_kantplank
Classification: 21.12 buitenwanden; niet constructief, spouwwanden (Uniformat)
Pset_WallCommon - ExtendToStructure: no; LoadBearing: no; IsExternal: yes

# IfcWall: Basic Wall:RBM_21_WA_betonnen_opstort_100mm, Basic Wall:RBM_21_WA_betonnen_opstort_100mm:2929713
In: -1 kelder
Type - PredefinedType: STANDARD; Material: RBM_f2_beton_ihwg C20-25 100 mm
Type - Pset_ElementShading - Roughness: 304.8 mm
Type - Pset_ProductRequirements - Category: Walls
Type - Pset_QuantityTakeOff - Reference: RBM_21_WA_betonnen_opstort_100mm
Type - Pset_ReinforcementBarPitchOfWall - Description: buitenwand, generiek; Reference: RBM_21_WA_betonnen_opstort_100mm
Type - Pset_WallCommon - IsExternal: no; Reference: RBM_21_WA_betonnen_opstort_100mm; ThermalTransmittance: 10.46 kg/K/s3
Classification: 21.10 buitenwanden; niet constructief, algemeen (verzamelniveau) (Uniformat); Material: RBM_f2_beton_ihwg C20-25
Pset_WallCommon - ExtendToStructure: no; LoadBearing: no; IsExternal: yes

# IfcWall: Basic Wall:RBM_21_WA_dakrand/pas strook_rockpanel (2)
Type - PredefinedType: STANDARD; Material: steenachtig_ntb_plaat_antraciet 8 mm, hout_vuren_regel 35 mm, hout_vuren_regel 35 mm, isolatie_steenwol_hsb_270 138 mm
Type - Pset_ElementShading - Roughness: 304.8 mm
Type - Pset_ProductRequirements - Category: Walls
Type - Pset_QuantityTakeOff - Reference: RBM_21_WA_dakrand/pas strook_rockpanel
Type - Pset_ReinforcementBarPitchOfWall - Description: isolatie, resolschuim; Reference: RBM_21_WA_dakrand/pas strook_rockpanel
Type - Pset_WallCommon - IsExternal: no; Reference: RBM_21_WA_dakrand/pas strook_rockpanel
Classification: 21.11 buitenwanden; niet constructief, massieve wanden (Uniformat)
Pset_WallCommon - ExtendToStructure: no; LoadBearing: no; IsExternal: yes
Name (Basic Wall:RBM_21_WA_dakrand/pas strook_rockpanel:...) | In
1888479 | 02 tweede verdieping
2683869 | 03 dak

# IfcWall: Basic Wall:RBM_21_WA_dakrand_houten bekleding, Basic Wall:RBM_21_WA_dakrand_houten bekleding:2731481
In: 03 dak
Type - PredefinedType: STANDARD; Material: hout_accoya_schubben 30 mm, ISR_Luchtspouw 35 mm, ISR_Luchtspouw 35 mm, RBM_n7_isolatie_hsb_invulling 138 mm
Type - Pset_ElementShading - Roughness: 304.8 mm
Type - Pset_ProductRequirements - Category: Walls
Type - Pset_QuantityTakeOff - Reference: RBM_21_WA_dakrand_houten bekleding
Type - Pset_ReinforcementBarPitchOfWall - Description: isolatie, resolschuim; Reference: RBM_21_WA_dakrand_houten bekleding
Type - Pset_WallCommon - IsExternal: no; Reference: RBM_21_WA_dakrand_houten bekleding
Classification: 21.11 buitenwanden; niet constructief, massieve wanden (Uniformat); Material: hout_accoya_schubben, ISR_Luchtspouw (2), RBM_n7_isolatie_hsb_invulling
Pset_WallCommon - ExtendToStructure: no; LoadBearing: no; IsExternal: yes

# IfcWall: Basic Wall:RBM_21_WA_dakrand_rockpanel_uitvullen, Basic Wall:RBM_21_WA_dakrand_rockpanel_uitvullen:2735765
In: 03 dak
Type - PredefinedType: STANDARD; Material: steenachtig_ntb_plaat_antraciet 8 mm, ISR_Luchtspouw 22 mm, ISR_Luchtspouw 35 mm, ISR_Luchtspouw 35 mm, isolatie_steenwol_hsb_270 138 mm
Type - Pset_ElementShading - Roughness: 304.8 mm
Type - Pset_ProductRequirements - Category: Walls
Type - Pset_QuantityTakeOff - Reference: RBM_21_WA_dakrand_rockpanel_uitvullen
Type - Pset_ReinforcementBarPitchOfWall - Description: isolatie, resolschuim; Reference: RBM_21_WA_dakrand_rockpanel_uitvullen
Type - Pset_WallCommon - IsExternal: no; Reference: RBM_21_WA_dakrand_rockpanel_uitvullen
Classification: 21.12 buitenwanden; niet constructief, spouwwanden (Uniformat); Material: steenachtig_ntb_plaat_antraciet, ISR_Luchtspouw (3), isolatie_steenwol_hsb_270
Pset_WallCommon - ExtendToStructure: no; LoadBearing: no; IsExternal: yes

# IfcWall: Basic Wall:RBM_21_WA_gevelbekleding op regelwerk_100mm (6)
Type - PredefinedType: STANDARD; Material: hout_accoya_schubben 30 mm, hout_vuren_regel 35 mm, hout_vuren_regel 35 mm
Type - Pset_ElementShading - Roughness: 304.8 mm
Type - Pset_ProductRequirements - Category: Walls
Type - Pset_QuantityTakeOff - Reference: RBM_21_WA_gevelbekleding op regelwerk_100mm
Type - Pset_ReinforcementBarPitchOfWall - Description: buitenwand, generiek; Reference: RBM_21_WA_gevelbekleding op regelwerk_100mm
Type - Pset_WallCommon - IsExternal: no; Reference: RBM_21_WA_gevelbekleding op regelwerk_100mm
Classification: 21.10 buitenwanden; niet constructief, algemeen (verzamelniveau) (Uniformat)
Pset_WallCommon - ExtendToStructure: no; LoadBearing: no; IsExternal: yes
Name (Basic Wall:RBM_21_WA_gevelbekleding op regelwerk_100mm:...) | In
2516713 | 01 eerste verdieping
2523123 | 00 begane grond
2745446 | 00 begane grond
2899968 | 01 eerste verdieping
2900441 | 01 eerste verdieping
2906478 | 00 begane grond

# IfcWall: Basic Wall:RBM_21_WA_hsb_288mm (3)
Type - PredefinedType: STANDARD; Material: isolatie_steenwol_hsb_270 270 mm, RBM_i4_multiplex_beplating 18 mm
Type - Pset_ElementShading - Roughness: 304.8 mm
Type - Pset_ProductRequirements - Category: Walls
Type - Pset_QuantityTakeOff - Reference: RBM_21_WA_hsb_288mm
Type - Pset_ReinforcementBarPitchOfWall - Description: hsb element 196mm, buitenafwerking: osb plaat met wind- en waterkerende folie, binnenwafwerking: osb plaat in het zicht; Reference: RBM_21_WA_hsb_288mm
Type - Pset_WallCommon - IsExternal: no; Reference: RBM_21_WA_hsb_288mm; ThermalTransmittance: 5.88889 kg/K/s3
Classification: 21.22 buitenwanden; constructief, spouwwanden (Uniformat)
Pset_WallCommon - LoadBearing: no; IsExternal: yes
Name (Basic Wall:RBM_21_WA_hsb_288mm:...) | In | ExtendToStructure
1653871 | 02 tweede verdieping | no | Material: RBM_n9_folie_do_wk, isolatie_steenwol_hsb_270, RBM_n9_folie_dd, RBM_i4_multiplex_beplating
1886117 | 00 begane grond | yes
1887044 | 01 eerste verdieping | no

# IfcWallStandardCase: Basic Wall:20_RBM_WA_betonnen_opstort_150mm (3)
In: -1 kelder
Type - PredefinedType: STANDARD; Material: RBM_f2_beton_ihwg C20-25 150 mm
Type - Pset_ElementShading - Roughness: 304.8 mm
Type - Pset_ProductRequirements - Category: Walls
Type - Pset_QuantityTakeOff - Reference: 20_RBM_WA_betonnen_opstort_150mm
Type - Pset_ReinforcementBarPitchOfWall - Description: buitenwand, generiek; Reference: 20_RBM_WA_betonnen_opstort_150mm
Type - Pset_WallCommon - IsExternal: no; Reference: 20_RBM_WA_betonnen_opstort_150mm; ThermalTransmittance: 6.97333 kg/K/s3
Classification: 21.10 buitenwanden; niet constructief, algemeen (verzamelniveau) (Uniformat)
Pset_WallCommon - ExtendToStructure: no; LoadBearing: no; IsExternal: yes
Name (Basic Wall:20_RBM_WA_betonnen_opstort_150mm:...)
2928191
2929253
2934676

# IfcWallStandardCase: Basic Wall:21_RBM_WA_hsb_270mm + rockpanel +afwerking gips binnen, Basic Wall:21_RBM_WA_hsb_270mm + rockpanel +afwerking gips binnen:2732826
In: 02 tweede verdieping
Type - PredefinedType: STANDARD; Material: steenachtig_ntb_plaat_antraciet 8 mm, ISR_Luchtspouw 35 mm, ISR_Luchtspouw 35 mm, isolatie_steenwol_hsb_270 270 mm, RBM_i4_multiplex_beplating 18 mm, RBM_f7_gips_beplating wand 12.5 mm
Type - Pset_ElementShading - Roughness: 304.8 mm
Type - Pset_ProductRequirements - Category: Walls
Type - Pset_QuantityTakeOff - Reference: 21_RBM_WA_hsb_270mm + rockpanel +afwerking gips binnen
Type - Pset_ReinforcementBarPitchOfWall - Description: hsb element 196mm, buitenafwerking: osb plaat met wind- en waterkerende folie, binnenwafwerking: osb plaat in het zicht; Reference: 21_RBM_WA_hsb_270mm + rockpanel +afwerking gips binnen
Type - Pset_WallCommon - IsExternal: no; Reference: 21_RBM_WA_hsb_270mm + rockpanel +afwerking gips binnen; ThermalTransmittance: 5.88889 kg/K/s3
Classification: 21.13 buitenwanden; niet constructief, systeemwanden (Uniformat)
Pset_WallCommon - ExtendToStructure: no; LoadBearing: no; IsExternal: yes

# IfcWallStandardCase: Basic Wall:21_RBM_WA_hsb_270mm - geïsoleerd (3)
In: 00 begane grond
Type - PredefinedType: STANDARD; Material: isolatie_steenwol_hsb_270 270 mm, RBM_i4_multiplex_beplating 18 mm
Type - Pset_ElementShading - Roughness: 304.8 mm
Type - Pset_ProductRequirements - Category: Walls
Type - Pset_QuantityTakeOff - Reference: 21_RBM_WA_hsb_270mm - geïsoleerd
Type - Pset_ReinforcementBarPitchOfWall - Description: hsb element 196mm, buitenafwerking: osb plaat met wind- en waterkerende folie, binnenwafwerking: osb plaat in het zicht; Reference: 21_RBM_WA_hsb_270mm - geïsoleerd
Type - Pset_WallCommon - IsExternal: no; Reference: 21_RBM_WA_hsb_270mm - geïsoleerd; ThermalTransmittance: 5.88889 kg/K/s3
Classification: 21.22 buitenwanden; constructief, spouwwanden (Uniformat)
Pset_WallCommon - ExtendToStructure: no; LoadBearing: no; IsExternal: yes
Name (Basic Wall:21_RBM_WA_hsb_270mm - geïsoleerd:...)
1643321
1778975
2744418

# IfcWallStandardCase: Basic Wall:21_RBM_WA_isolatie_PIR_120mm, Basic Wall:21_RBM_WA_isolatie_PIR_120mm:2937708
In: 00 begane grond
Type - PredefinedType: STANDARD; Material: RBM_n7_isolatie_PIR 120 mm
Type - Pset_ElementShading - Roughness: 304.8 mm
Type - Pset_ProductRequirements - Category: Walls
Type - Pset_QuantityTakeOff - Reference: 21_RBM_WA_isolatie_PIR_120mm
Type - Pset_ReinforcementBarPitchOfWall - Description: isolatie, resolschuim; Reference: 21_RBM_WA_isolatie_PIR_120mm
Type - Pset_WallCommon - IsExternal: no; Reference: 21_RBM_WA_isolatie_PIR_120mm; ThermalTransmittance: 0.25 kg/K/s3
Classification: 21.12 buitenwanden; niet constructief, spouwwanden (Uniformat)
Pset_WallCommon - ExtendToStructure: no; LoadBearing: no; IsExternal: yes

# IfcWallStandardCase: Basic Wall:21_RBM_WA_passtrook_BU (3)
In: 01 eerste verdieping
Type - PredefinedType: STANDARD; Material: RBM_n7_isolatie_hsb_invulling 138 mm
Type - Pset_ElementShading - Roughness: 304.8 mm
Type - Pset_ProductRequirements - Category: Walls
Type - Pset_ReinforcementBarPitchOfWall - Description: isolatie, resolschuim
Type - Pset_WallCommon - IsExternal: no
Classification: 21.22 buitenwanden; constructief, spouwwanden (Uniformat)
Pset_WallCommon - ExtendToStructure: no; LoadBearing: no; IsExternal: yes
Name (Basic Wall:21_RBM_WA_passtrook_BU:...)
1887039
1887043
2521709

# IfcWallStandardCase: Basic Wall:21_hsb_100mm, Basic Wall:21_hsb_100mm:1782067
In: 00 begane grond
Type - PredefinedType: STANDARD; Material: steenachtig_ntb_plaat_antraciet 20 mm, RBM_n7_isolatie_hsb_100 100 mm
Type - Pset_ElementShading - Roughness: 304.8 mm
Type - Pset_ProductRequirements - Category: Walls
Type - Pset_QuantityTakeOff - Reference: 21_hsb_100mm
Type - Pset_ReinforcementBarPitchOfWall - Reference: 21_hsb_100mm
Type - Pset_WallCommon - IsExternal: no; Reference: 21_hsb_100mm
Classification: 22 binnenwanden (Uniformat)
Pset_QuantityTakeOff - sets with these values: 2
Pset_WallCommon - ExtendToStructure: no; LoadBearing: no

# IfcWallStandardCase: Basic Wall:22_RBM_WA_metalstud_70_12.5-45-12.5 (2)
Type - PredefinedType: STANDARD; Material: RBM_f7_gips_beplating wand 12.5 mm, RBM_n7_isolatie_MS45 45 mm, RBM_f7_gips_beplating wand 12.5 mm
Type - Pset_ElementShading - Roughness: 304.8 mm
Type - Pset_ProductRequirements - Category: Walls
Type - Pset_QuantityTakeOff - Reference: 22_RBM_WA_metalstud_70_12.5-45-12.5
Type - Pset_ReinforcementBarPitchOfWall - Description: metalstudwand; Reference: 22_RBM_WA_metalstud_70_12.5-45-12.5
Type - Pset_WallCommon - IsExternal: no; Reference: 22_RBM_WA_metalstud_70_12.5-45-12.5
Classification: 22.13 binnenwanden; niet constructief, systeemwanden; vast (Uniformat)
Pset_WallCommon - LoadBearing: no; IsExternal: yes
Name (Basic Wall:22_RBM_WA_metalstud_70_12.5-45-12.5:...) | In | ExtendToStructure
1749284 | 01 eerste verdieping | yes
1786324 | 00 begane grond | no

# IfcWallStandardCase: Basic Wall:22_RBM_WA_ontwerpwand-40mm (4)
In: 00 begane grond
Type - PredefinedType: STANDARD; Material: <Unnamed> 50 mm
Type - Pset_ElementShading - Roughness: 304.8 mm
Type - Pset_ProductRequirements - Category: Walls
Type - Pset_QuantityTakeOff - Reference: 22_RBM_WA_ontwerpwand-40mm
Type - Pset_ReinforcementBarPitchOfWall - Description: buitenwand, generiek; Reference: 22_RBM_WA_ontwerpwand-40mm
Type - Pset_WallCommon - IsExternal: no; Reference: 22_RBM_WA_ontwerpwand-40mm
Classification: 22.21 binnenwanden; constructief, massieve wanden (Uniformat); Group: Model Group:Lift:2178208
Pset_WallCommon - LoadBearing: no; IsExternal: yes
Name (Basic Wall:22_RBM_WA_ontwerpwand-40mm:...) | ExtendToStructure
1770855 | yes
1770856 | yes
2177971 | no
2178088 | yes

# IfcWallStandardCase: Basic Wall:22_RBM_WA_ontwerpwand-40mm_transparant (3)
In: 00 begane grond
Type - PredefinedType: STANDARD; Material: RBM_o1_glas_helder 50 mm
Type - Pset_ElementShading - Roughness: 304.8 mm
Type - Pset_ProductRequirements - Category: Walls
Type - Pset_QuantityTakeOff - Reference: 22_RBM_WA_ontwerpwand-40mm_transparant
Type - Pset_ReinforcementBarPitchOfWall - Description: buitenwand, generiek; Reference: 22_RBM_WA_ontwerpwand-40mm_transparant
Type - Pset_WallCommon - IsExternal: no; Reference: 22_RBM_WA_ontwerpwand-40mm_transparant; ThermalTransmittance: 22 kg/K/s3
Classification: 22.10 binnenwanden; niet constructief, algemeen (verzamelniveau) (Uniformat); Group: Model Group:Lift:2178208
Pset_WallCommon - LoadBearing: no; ExtendToStructure: yes; IsExternal: yes
Name (Basic Wall:22_RBM_WA_ontwerpwand-40mm_transparant:...)
1770853
1770854
2178169

# IfcWallStandardCase: Basic Wall:22_WA_hsb_binnenwand_306mm (3)
In: 00 begane grond
Type - PredefinedType: STANDARD; Material: RBM_i4_multiplex_beplating 18 mm, isolatie_steenwol_hsb_270 270 mm, RBM_i4_multiplex_beplating 18 mm
Type - Pset_ElementShading - Roughness: 304.8 mm
Type - Pset_ProductRequirements - Category: Walls
Type - Pset_QuantityTakeOff - Reference: 22_WA_hsb_binnenwand_306mm
Type - Pset_ReinforcementBarPitchOfWall - Reference: 22_WA_hsb_binnenwand_306mm
Type - Pset_WallCommon - IsExternal: no; Reference: 22_WA_hsb_binnenwand_306mm; ThermalTransmittance: 2.94444 kg/K/s3
Classification: 22.20 binnenwanden; constructief, algemeen (verzamelniveau) (Uniformat)
Pset_QuantityTakeOff - sets with these values: 2
Pset_WallCommon - ExtendToStructure: no; LoadBearing: no
Name (Basic Wall:22_WA_hsb_binnenwand_306mm:...)
1642337
1888207
2505107

# IfcWallStandardCase: Basic Wall:22_hsb_270 passtrook (3)
In: 00 begane grond
Type - PredefinedType: STANDARD; Material: isolatie_steenwol_hsb_270 132 mm, RBM_i4_multiplex_beplating 18 mm
Type - Pset_ElementShading - Roughness: 304.8 mm
Type - Pset_ProductRequirements - Category: Walls
Type - Pset_QuantityTakeOff - Reference: 22_hsb_270 passtrook
Type - Pset_ReinforcementBarPitchOfWall - Reference: 22_hsb_270 passtrook
Type - Pset_WallCommon - IsExternal: no; Reference: 22_hsb_270 passtrook; ThermalTransmittance: 5.88889 kg/K/s3
Classification: 22.20 binnenwanden; constructief, algemeen (verzamelniveau) (Uniformat)
Pset_QuantityTakeOff - sets with these values: 2
Pset_WallCommon - LoadBearing: no
Name (Basic Wall:22_hsb_270 passtrook:...) | ExtendToStructure
2736768 | yes
2748201 | no
2748499 | no

# IfcWallStandardCase: Basic Wall:22_hsb_270 passtrook + 6, Basic Wall:22_hsb_270 passtrook + 6:2812115
In: 02 tweede verdieping
Type - PredefinedType: STANDARD; Material: isolatie_steenwol_hsb_270 138 mm, RBM_i4_multiplex_beplating 18 mm
Type - Pset_ElementShading - Roughness: 304.8 mm
Type - Pset_ProductRequirements - Category: Walls
Type - Pset_QuantityTakeOff - Reference: 22_hsb_270 passtrook + 6
Type - Pset_ReinforcementBarPitchOfWall - Reference: 22_hsb_270 passtrook + 6
Type - Pset_WallCommon - IsExternal: no; Reference: 22_hsb_270 passtrook + 6; ThermalTransmittance: 5.88889 kg/K/s3
Classification: 22.20 binnenwanden; constructief, algemeen (verzamelniveau) (Uniformat)
Pset_QuantityTakeOff - sets with these values: 2
Pset_WallCommon - ExtendToStructure: no; LoadBearing: no

# IfcWallStandardCase: Basic Wall:22_hsb_270 passtrook + gips (3)
Type - PredefinedType: STANDARD; Material: isolatie_steenwol_hsb_270 132 mm, RBM_i4_multiplex_beplating 18 mm, RBM_f7_gips_beplating wand 12.5 mm
Type - Pset_ElementShading - Roughness: 304.8 mm
Type - Pset_ProductRequirements - Category: Walls
Type - Pset_QuantityTakeOff - Reference: 22_hsb_270 passtrook + gips
Type - Pset_ReinforcementBarPitchOfWall - Reference: 22_hsb_270 passtrook + gips
Type - Pset_WallCommon - IsExternal: no; Reference: 22_hsb_270 passtrook + gips; ThermalTransmittance: 5.88889 kg/K/s3
Classification: 22.20 binnenwanden; constructief, algemeen (verzamelniveau) (Uniformat)
Pset_QuantityTakeOff - sets with these values: 2
Pset_WallCommon - ExtendToStructure: no; LoadBearing: no
Name (Basic Wall:22_hsb_270 passtrook + gips:...) | In
2752296 | 02 tweede verdieping
2752812 | 02 tweede verdieping
2753440 | 01 eerste verdieping

# IfcWallStandardCase: Basic Wall:22_hsb_binnenwand_gips_318,5mm (6)
Type - PredefinedType: STANDARD; Material: RBM_f7_gips_beplating wand 12.5 mm, RBM_i4_multiplex_beplating 18 mm, isolatie_steenwol_hsb_270 270 mm, RBM_i4_multiplex_beplating 18 mm
Type - Pset_ElementShading - Roughness: 304.8 mm
Type - Pset_ProductRequirements - Category: Walls
Type - Pset_QuantityTakeOff - Reference: 22_hsb_binnenwand_gips_318,5mm
Type - Pset_ReinforcementBarPitchOfWall - Reference: 22_hsb_binnenwand_gips_318,5mm
Type - Pset_WallCommon - Reference: 22_hsb_binnenwand_gips_318,5mm; ThermalTransmittance: 2.94444 kg/K/s3; IsExternal: no
Classification: 22.20 binnenwanden; constructief, algemeen (verzamelniveau) (Uniformat)
Pset_QuantityTakeOff - sets with these values: 2
Pset_WallCommon - LoadBearing: no
Name (Basic Wall:22_hsb_binnenwand_gips_318,5mm:...) | In | ExtendToStructure
1641471 | 00 begane grond | no
1641685 | 00 begane grond | no
1653860 | 02 tweede verdieping | yes
1653861 | 01 eerste verdieping | yes
1660133 | 01 eerste verdieping | yes
1970625 | 00 begane grond | no

# IfcWallStandardCase: Basic Wall:RBM_21_WA_170mm_geïsoleerde_kantplank (14)
In: 00 begane grond
Type - PredefinedType: STANDARD; Material: geisoleerde cementvezelplaat 20 mm, RBM_n7_isolatie_resol 150 mm
Type - Pset_ElementShading - Roughness: 304.8 mm
Type - Pset_ProductRequirements - Category: Walls
Type - Pset_QuantityTakeOff - Reference: RBM_21_WA_170mm_geïsoleerde_kantplank
Type - Pset_ReinforcementBarPitchOfWall - Description: isolatie, resolschuim; Reference: RBM_21_WA_170mm_geïsoleerde_kantplank
Type - Pset_WallCommon - IsExternal: no; Reference: RBM_21_WA_170mm_geïsoleerde_kantplank
Classification: 21.12 buitenwanden; niet constructief, spouwwanden (Uniformat)
Pset_WallCommon - ExtendToStructure: no; LoadBearing: no; IsExternal: yes
Name (Basic Wall:RBM_21_WA_170mm_geïsoleerde_kantplank:...)
1886116
1886669
1886994
1887892
1887978
1887982
1888419
1972137
2047766
2361678
2640555
2640629
2640833
2935683

# IfcWallStandardCase: Basic Wall:RBM_21_WA_betonnen_opstort_100mm (2)
In: -1 kelder
Type - PredefinedType: STANDARD; Material: RBM_f2_beton_ihwg C20-25 100 mm
Type - Pset_ElementShading - Roughness: 304.8 mm
Type - Pset_ProductRequirements - Category: Walls
Type - Pset_QuantityTakeOff - Reference: RBM_21_WA_betonnen_opstort_100mm
Type - Pset_ReinforcementBarPitchOfWall - Description: buitenwand, generiek; Reference: RBM_21_WA_betonnen_opstort_100mm
Type - Pset_WallCommon - IsExternal: no; Reference: RBM_21_WA_betonnen_opstort_100mm; ThermalTransmittance: 10.46 kg/K/s3
Classification: 21.10 buitenwanden; niet constructief, algemeen (verzamelniveau) (Uniformat)
Pset_WallCommon - ExtendToStructure: no; LoadBearing: no; IsExternal: yes
Name (Basic Wall:RBM_21_WA_betonnen_opstort_100mm:...)
2929797
2930029

# IfcWallStandardCase: Basic Wall:RBM_21_WA_dakrand/pas strook_rockpanel (9)
Type - PredefinedType: STANDARD; Material: steenachtig_ntb_plaat_antraciet 8 mm, hout_vuren_regel 35 mm, hout_vuren_regel 35 mm, isolatie_steenwol_hsb_270 138 mm
Type - Pset_ElementShading - Roughness: 304.8 mm
Type - Pset_ProductRequirements - Category: Walls
Type - Pset_QuantityTakeOff - Reference: RBM_21_WA_dakrand/pas strook_rockpanel
Type - Pset_ReinforcementBarPitchOfWall - Description: isolatie, resolschuim; Reference: RBM_21_WA_dakrand/pas strook_rockpanel
Type - Pset_WallCommon - IsExternal: no; Reference: RBM_21_WA_dakrand/pas strook_rockpanel
Classification: 21.11 buitenwanden; niet constructief, massieve wanden (Uniformat)
Pset_WallCommon - ExtendToStructure: no; LoadBearing: no; IsExternal: yes
Name (Basic Wall:RBM_21_WA_dakrand/pas strook_rockpanel:...) | In
1886504 | 02 tweede verdieping
1889003 | 01 eerste verdieping
2654662 | 02 tweede verdieping
2681180 | 03 dak
2682410 | 03 dak
2684279 | 03 dak
2731676 | 03 dak
2731722 | 03 dak
2741240 | 02 tweede verdieping

# IfcWallStandardCase: Basic Wall:RBM_21_WA_dakrand_beplating_rockpanel (4)
In: 00 begane grond
Type - PredefinedType: STANDARD; Material: steenachtig_ntb_plaat_antraciet 8 mm, hout_vuren_regel 35 mm, hout_vuren_regel 35 mm
Type - Pset_ElementShading - Roughness: 304.8 mm
Type - Pset_ProductRequirements - Category: Walls
Type - Pset_QuantityTakeOff - Reference: RBM_21_WA_dakrand_beplating_rockpanel
Type - Pset_ReinforcementBarPitchOfWall - Description: isolatie, resolschuim; Reference: RBM_21_WA_dakrand_beplating_rockpanel
Type - Pset_WallCommon - IsExternal: no; Reference: RBM_21_WA_dakrand_beplating_rockpanel
Classification: 21.12 buitenwanden; niet constructief, spouwwanden (Uniformat)
Pset_WallCommon - ExtendToStructure: no; LoadBearing: no; IsExternal: yes
Name (Basic Wall:RBM_21_WA_dakrand_beplating_rockpanel:...)
2749810
2750308
2750965
2751185

# IfcWallStandardCase: Basic Wall:RBM_21_WA_gevelafwerking op regelwerk_100mm, Basic Wall:RBM_21_WA_gevelafwerking op regelwerk_100mm:2904174
In: 00 begane grond
Type - PredefinedType: STANDARD; Material: hout_accoya_schubben 30 mm, hout_vuren_regel 35 mm, hout_vuren_regel 35 mm
Type - Pset_ElementShading - Roughness: 304.8 mm
Type - Pset_ProductRequirements - Category: Walls
Type - Pset_QuantityTakeOff - Reference: RBM_21_WA_gevelafwerking op regelwerk_100mm
Type - Pset_ReinforcementBarPitchOfWall - Description: buitenwand, generiek; Reference: RBM_21_WA_gevelafwerking op regelwerk_100mm
Type - Pset_WallCommon - IsExternal: no; Reference: RBM_21_WA_gevelafwerking op regelwerk_100mm
Classification: 21.10 buitenwanden; niet constructief, algemeen (verzamelniveau) (Uniformat)
Pset_WallCommon - ExtendToStructure: no; LoadBearing: no; IsExternal: yes

# IfcWallStandardCase: Basic Wall:RBM_21_WA_gevelbekleding op regelwerk_100mm (24)
Type - PredefinedType: STANDARD; Material: hout_accoya_schubben 30 mm, hout_vuren_regel 35 mm, hout_vuren_regel 35 mm
Type - Pset_ElementShading - Roughness: 304.8 mm
Type - Pset_ProductRequirements - Category: Walls
Type - Pset_QuantityTakeOff - Reference: RBM_21_WA_gevelbekleding op regelwerk_100mm
Type - Pset_ReinforcementBarPitchOfWall - Description: buitenwand, generiek; Reference: RBM_21_WA_gevelbekleding op regelwerk_100mm
Type - Pset_WallCommon - IsExternal: no; Reference: RBM_21_WA_gevelbekleding op regelwerk_100mm
Classification: 21.10 buitenwanden; niet constructief, algemeen (verzamelniveau) (Uniformat)
Pset_WallCommon - ExtendToStructure: no; LoadBearing: no; IsExternal: yes
Name (Basic Wall:RBM_21_WA_gevelbekleding op regelwerk_100mm:...) | In
2511620 | 00 begane grond
2514147 | 00 begane grond
2514630 | 00 begane grond
2514782 | 00 begane grond
2515039 | 00 begane grond
2898391 | 00 begane grond
2898507 | 00 begane grond
2898665 | 00 begane grond
2898815 | 00 begane grond
2900293 | 01 eerste verdieping
2904270 | 00 begane grond
2904526 | 01 eerste verdieping
2904606 | 01 eerste verdieping
2907784 | 00 begane grond
2908448 | 00 begane grond
2909224 | 00 begane grond
2912548 | 00 begane grond
2912895 | 00 begane grond
2912990 | 00 begane grond
2913631 | 00 begane grond
2915802 | 01 eerste verdieping
2915879 | 01 eerste verdieping
2916025 | 01 eerste verdieping
2916380 | 01 eerste verdieping

# IfcWallStandardCase: Basic Wall:RBM_21_WA_hsb_ rockpanel_366mm (9)
Type - PredefinedType: STANDARD; Material: steenachtig_ntb_plaat_antraciet 8 mm, ISR_Luchtspouw 35 mm, ISR_Luchtspouw 35 mm, isolatie_steenwol_hsb_270 270 mm, RBM_i4_multiplex_beplating 18 mm
Type - Pset_ElementShading - Roughness: 304.8 mm
Type - Pset_ProductRequirements - Category: Walls
Type - Pset_QuantityTakeOff - Reference: RBM_21_WA_hsb_ rockpanel_366mm
Type - Pset_ReinforcementBarPitchOfWall - Description: hsb element 196mm, buitenafwerking: osb plaat met wind- en waterkerende folie, binnenwafwerking: osb plaat in het zicht; Reference: RBM_21_WA_hsb_ rockpanel_366mm
Type - Pset_WallCommon - IsExternal: no; Reference: RBM_21_WA_hsb_ rockpanel_366mm; ThermalTransmittance: 5.88889 kg/K/s3
Classification: 21.22 buitenwanden; constructief, spouwwanden (Uniformat)
Pset_WallCommon - ExtendToStructure: no; LoadBearing: no; IsExternal: yes
Name (Basic Wall:RBM_21_WA_hsb_ rockpanel_366mm:...) | In
1886505 | 02 tweede verdieping
1886577 | 02 tweede verdieping
1887979 | 00 begane grond
1887983 | 00 begane grond
1888420 | 00 begane grond
1888480 | 02 tweede verdieping
1972138 | 00 begane grond
2454753 | 02 tweede verdieping
2754429 | 01 eerste verdieping

# IfcWallStandardCase: Basic Wall:RBM_21_WA_hsb_270mm - niet geïsoleerd (3)
In: 00 begane grond
Type - PredefinedType: STANDARD; Material: ISR_Luchtspouw 270 mm, RBM_i4_multiplex_beplating 18 mm
Type - Pset_ElementShading - Roughness: 304.8 mm
Type - Pset_ProductRequirements - Category: Walls
Type - Pset_QuantityTakeOff - Reference: RBM_21_WA_hsb_270mm - niet geïsoleerd
Type - Pset_ReinforcementBarPitchOfWall - Description: hsb element 196mm, buitenafwerking: osb plaat met wind- en waterkerende folie, binnenwafwerking: osb plaat in het zicht; Reference: RBM_21_WA_hsb_270mm - niet geïsoleerd
Type - Pset_WallCommon - IsExternal: no; Reference: RBM_21_WA_hsb_270mm - niet geïsoleerd; ThermalTransmittance: 5.88889 kg/K/s3
Classification: 21.13 buitenwanden; niet constructief, systeemwanden (Uniformat)
Pset_WallCommon - ExtendToStructure: no; LoadBearing: no; IsExternal: yes
Name (Basic Wall:RBM_21_WA_hsb_270mm - niet geïsoleerd:...)
1977456
1977517
2740495

# IfcWallStandardCase: Basic Wall:RBM_21_WA_hsb_288mm (7)
Type - PredefinedType: STANDARD; Material: isolatie_steenwol_hsb_270 270 mm, RBM_i4_multiplex_beplating 18 mm
Type - Pset_ElementShading - Roughness: 304.8 mm
Type - Pset_ProductRequirements - Category: Walls
Type - Pset_QuantityTakeOff - Reference: RBM_21_WA_hsb_288mm
Type - Pset_ReinforcementBarPitchOfWall - Description: hsb element 196mm, buitenafwerking: osb plaat met wind- en waterkerende folie, binnenwafwerking: osb plaat in het zicht; Reference: RBM_21_WA_hsb_288mm
Type - Pset_WallCommon - IsExternal: no; Reference: RBM_21_WA_hsb_288mm; ThermalTransmittance: 5.88889 kg/K/s3
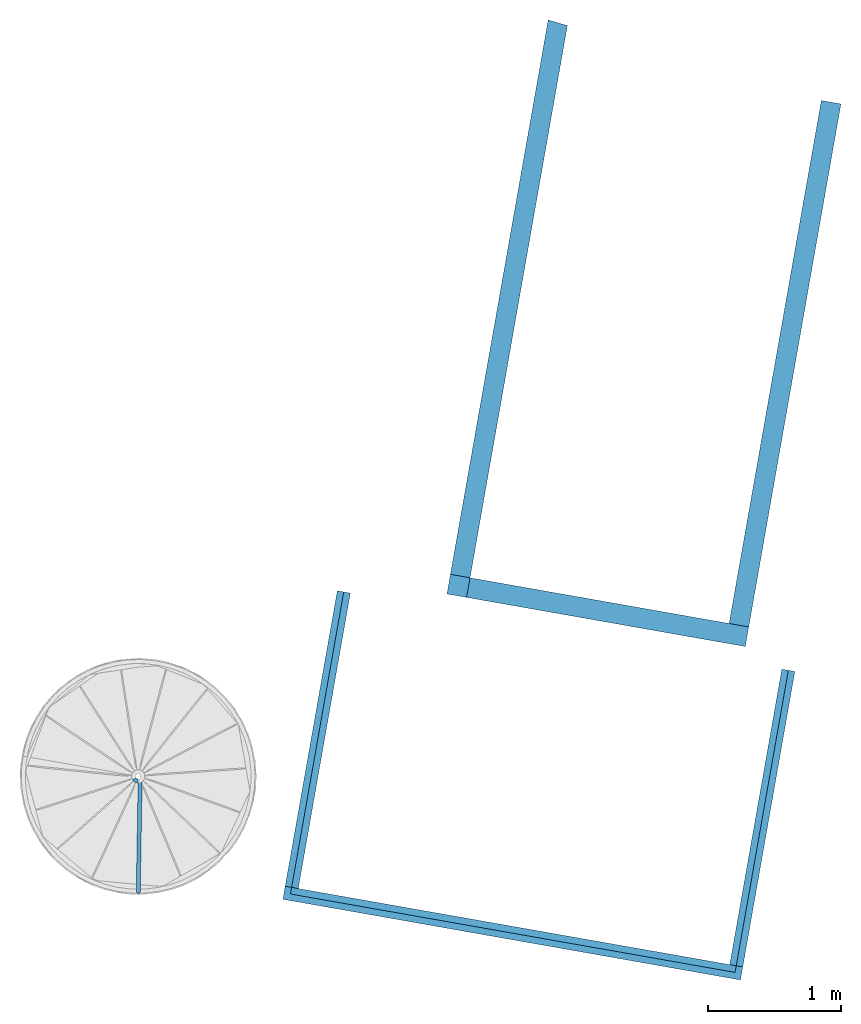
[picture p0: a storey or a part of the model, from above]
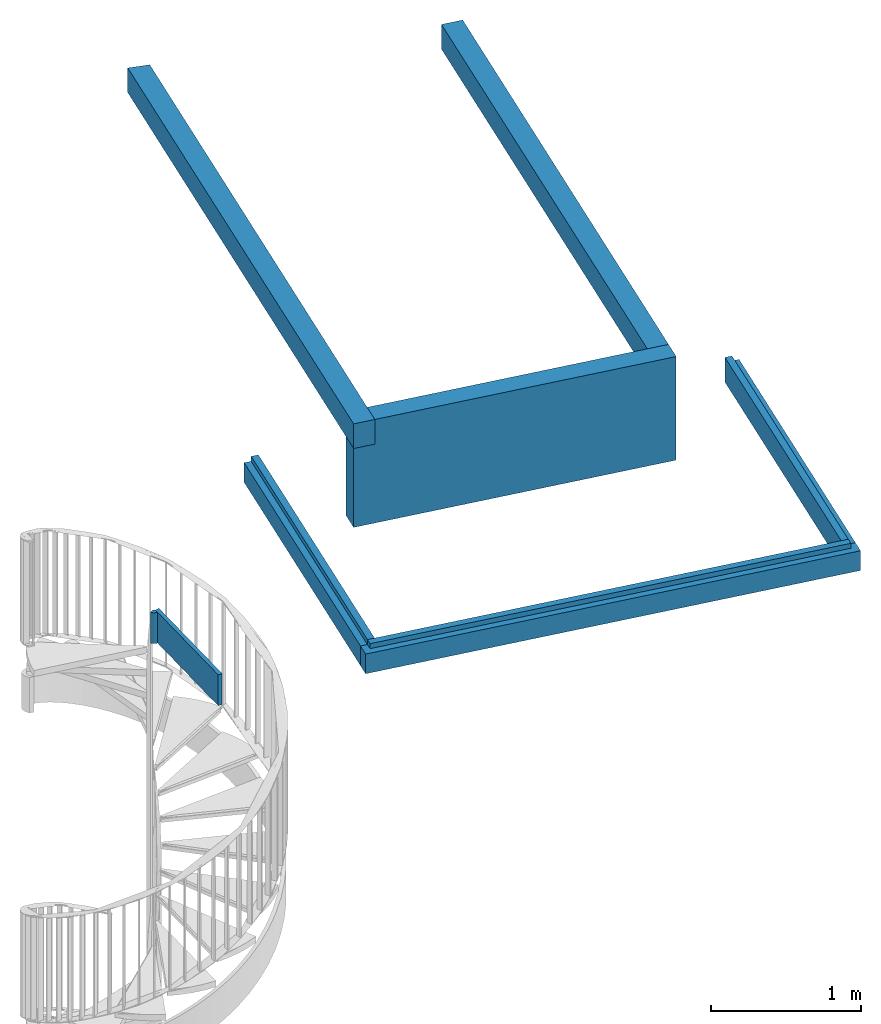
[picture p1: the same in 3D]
Properties of the parts of a building model (IFC2X3), part 3 of 3

# IfcWallStandardCase: Basic Wall:RBM_21_WA_hsb_288mm (7)
Classification: 21.22 buitenwanden; constructief, spouwwanden (Uniformat)
Pset_WallCommon - LoadBearing: no; IsExternal: yes
Name (Basic Wall:RBM_21_WA_hsb_288mm:...) | In | ExtendToStructure
1886670 | 00 begane grond | no
1886995 | 00 begane grond | no
1887040 | 01 eerste verdieping | yes
1887893 | 00 begane grond | no
2520142 | 00 begane grond | no
2520221 | 00 begane grond | no
2747179 | 00 begane grond | no

# IfcWallStandardCase: Basic Wall:WA_22_metalstud_binnenwand_100mm (14)
Type - PredefinedType: STANDARD; Material: RBM_a_metalstudwand 100 mm
Type - Pset_ElementShading - Roughness: 304.8 mm
Type - Pset_ProductRequirements - Category: Walls
Type - Pset_QuantityTakeOff - Reference: WA_22_metalstud_binnenwand_100mm
Type - Pset_ReinforcementBarPitchOfWall - Reference: WA_22_metalstud_binnenwand_100mm
Type - Pset_WallCommon - IsExternal: no; Reference: WA_22_metalstud_binnenwand_100mm
Classification: 22.10 binnenwanden; niet constructief, algemeen (verzamelniveau) (Uniformat)
Pset_QuantityTakeOff - sets with these values: 2
Pset_WallCommon - LoadBearing: no
Name (Basic Wall:WA_22_metalstud_binnenwand_100mm:...) | In | ExtendToStructure
1641766 | 00 begane grond | yes
1641830 | 00 begane grond | no
1641944 | 00 begane grond | no
1642114 | 00 begane grond | yes
1657728 | 00 begane grond | no
1657769 | 00 begane grond | yes
1657880 | 01 eerste verdieping | yes
1657975 | 01 eerste verdieping | yes
1658055 | 01 eerste verdieping | yes
1658157 | 01 eerste verdieping | yes
1658265 | 01 eerste verdieping | yes
1748973 | 01 eerste verdieping | yes
1749211 | 01 eerste verdieping | yes
2391560 | 01 eerste verdieping | yes

# IfcWindow: glas 2 (12)
Type - ParameterTakesPrecedence: no; Sizeable: no; Classification: 31.11 buitenwandopeningen; niet gevuld, daglichtopeningen (Uniformat); Material: o1_glas
Pset_ManufacturerTypeInformation - Manufacturer: ITANNEX
Pset_ProductRequirements - Category: Windows
Pset_QuantityTakeOff - Reference: glas 2
Pset_WindowCommon - IsExternal: no; Reference: glas 2
Name (WI_subvak:glas 2:...) | In | OverallHeight (mm) | OverallWidth (mm) | Group
1771785 | 00 begane grond | 2173 | 526.5 | Model Group:H05:2174889
1771786 | 00 begane grond | 2173 | 526.5 | Model Group:H05:2174889
1773415 | 02 tweede verdieping | 2173 | 476.5 | Model Group:32_dubbele deur:2147310
1773416 | 02 tweede verdieping | 2173 | 476.5 | Model Group:32_dubbele deur:2147310
1774062 | 00 begane grond | 2173 | 526.5
1774063 | 00 begane grond | 2173 | 526.5
2317231 | 00 begane grond | 2206.5 | 821.227 | Model Group:vliesgevel C:2317233
2317232 | 00 begane grond | 2206.5 | 821.227 | Model Group:vliesgevel C:2317233
2536678 | 00 begane grond | 2051.17 | 969.01 | Model Group:Vliesgevel B:2773624
2536679 | 00 begane grond | 2051.17 | 969.01 | Model Group:Vliesgevel B:2773624
2940449 | 00 begane grond | 2206.5 | 882.348 | Model Group:vliesgevel A:2917414
2940450 | 00 begane grond | 2206.5 | 882.348 | Model Group:vliesgevel A:2917414
